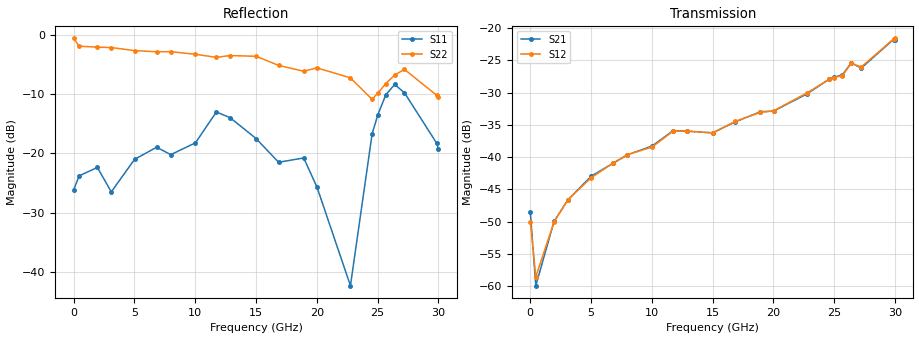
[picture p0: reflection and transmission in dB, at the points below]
!Agilent Technologies,E8364B,MY43040894,A.07.50.67
!Agilent E8364B: A.07.50.67
!Date: Wednesday, July 10, 2019 11:57:47
!Correction: S11(Full 2 Port(1,2))
!S21(Full 2 Port(1,2))
!S12(Full 2 Port(1,2))
!S22(Full 2 Port(1,2))
!S2P File: Measurements: S11, S21, S12, S22:
# Hz S  dB  R 50
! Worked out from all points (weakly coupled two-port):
!   1601 points, 10 MHz to 30 GHz, reference 50 ohm
!   highest |S21| = -21.77 dB at 29.87 GHz (marker M1); lowest = -59.9 dB at 459.9 MHz (marker M2)
!   lowest |S11| = -42.4 dB at 22.76 GHz (marker M3), VSWR 1.02, Z = 49.5 - j0.538 ohm
!   |S11| at or under -10 dB: start of sweep to 25.69 GHz; 27.27 GHz to 28.21 GHz (941.7 MHz wide, 3.4 % of centre); 28.36 GHz to end of sweep
!   |S22| runs from -11.1 to -0.5 dB; largest |S21 - S12| = 0.0056
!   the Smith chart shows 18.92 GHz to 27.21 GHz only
!   S11 on the Smith chart (normalised r, x): 18.92 GHz: 0.87, +0.11; 24.55 GHz: 1.34, -0.06; 25.67 GHz: 0.72, -0.48; 26.4 GHz: 0.45, -0.07; 27.21 GHz: 0.60, +0.35
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1e7  -26.16 -7.2  -48.58 -7.6  -50.07 101.3  -0.55 -49.2
4.5985e8  -23.79 -29.2  -59.93 6.7  -58.55 1.0  -1.87 170.5
1.95935e9  -22.38 -175.7  -49.95 -58.8  -50.04 -58.4  -2.04 7.4
3.102719e9  -26.51 81.3  -46.62 -124.4  -46.59 -123.5  -2.10 -98.9
5.014581e9  -21.01 -81.8  -42.95 119.4  -43.19 118.7  -2.62 85.5
6.832725e9  -18.96 109.6  -40.93 7.2  -40.89 6.1  -2.81 -79.7
7.994838e9  -20.21 43.3  -39.65 -69.7  -39.62 -68.6  -2.80 173.4
1.001916e10  -18.22 173.9  -38.28 161.3  -38.44 160.2  -3.24 -10.0
1.174359e10  -13.00 58.8  -35.90 47.0  -35.98 47.7  -3.76 -168.4
1.286821e10  -13.96 -14.2  -35.99 -34.1  -35.94 -33.1  -3.46 83.4
1.5005e10  -17.49 -126.9  -36.23 -172.4  -36.26 -173.8  -3.58 -103.1
1.686063e10  -21.50 -2.6  -34.53 67.8  -34.45 68.7  -5.12 96.9
1.892244e10  -20.77 134.6  -32.97 -76.1  -33.07 -76.5  -6.11 -120.8
2.000958e10  -25.68 -18.4  -32.86 -151.1  -32.82 -151.4  -5.54 138.7
2.276491e10  -42.37 -134.4  -30.19 30.2  -30.04 30.6  -7.23 -90.9
2.454557e10  -16.72 -8.3  -27.96 -101.3  -27.96 -101.9  -10.85 60.2
2.501416e10  -13.50 -47.1  -27.61 -136.3  -27.66 -136.9  -9.82 4.8
2.567019e10  -10.10 -104.7  -27.23 177.2  -27.35 176.6  -8.21 -62.4
2.64012e10  -8.35 -170.0  -25.37 120.6  -25.44 121.1  -6.75 -127.7
2.720718e10  -9.75 126.8  -26.21 52.0  -26.05 52.3  -5.80 163.4
2.986879e10  -18.32 -6.0  -21.77 -121.9  -21.68 -120.7  -10.20 -80.6
3e10  -19.29 -13.6  -21.79 -131.1  -21.59 -129.8  -10.48 -92.0
